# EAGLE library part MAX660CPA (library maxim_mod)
Charge-pump VOLTAGE CONVERTER

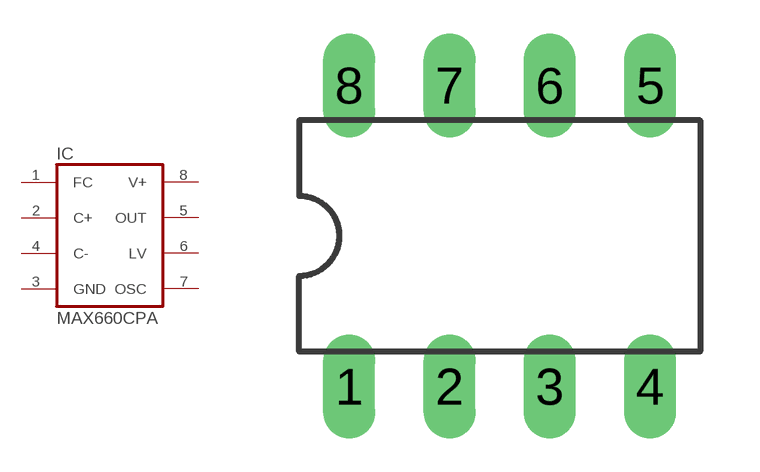
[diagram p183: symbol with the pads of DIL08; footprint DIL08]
Designator prefix IC

## MAX660CPA  [DIL08]
1  FC  in
2  C+  pas
3  GND  pwr
4  C-  pas
5  OUT  sup
6  LV  pas
7  OSC  out
8  V+  pwr

## Footprint DIL08 (pad centres in mm)
Dual In Line Package
drill 0.813 long: 1 -3.81,-3.81; 2 -1.27,-3.81; 3 1.27,-3.81; 4 3.81,-3.81; 5 3.81,3.81; 6 1.27,3.81; 7 -1.27,3.81; 8 -3.81,3.81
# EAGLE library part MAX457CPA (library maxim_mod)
VIDEO AMPLIFIER

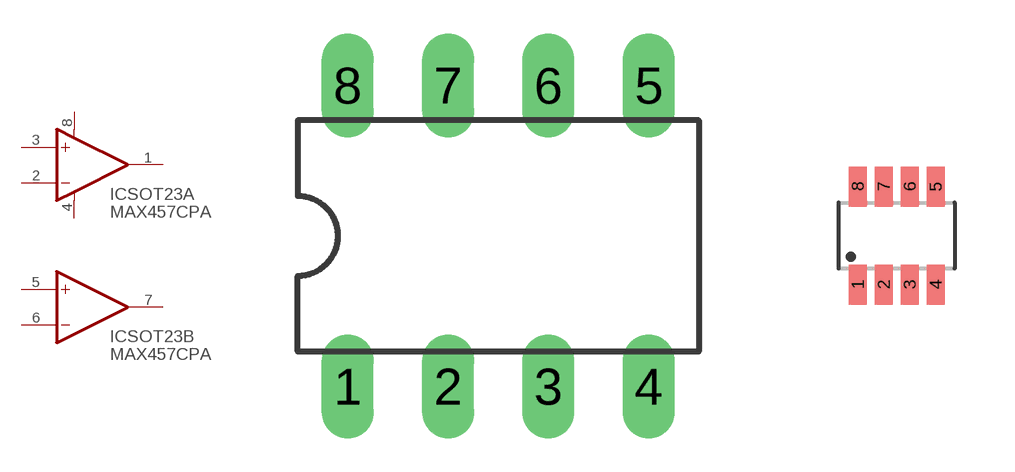
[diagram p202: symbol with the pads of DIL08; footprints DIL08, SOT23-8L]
Designator prefix ICSOT23; gates A=OPUB B=OP

## MAX457CPA  [DIL08]
1  A:OUT  out
2  A:-IN  in
3  A:+IN  in
4  A:V-  pwr
5  B:+IN  in
6  B:-IN  in
7  B:OUT  out
8  A:V+  pwr

## MAX457CPASOT23_8  [SOT23-8L]
Pads as for DIL08

## Footprint DIL08 (pad centres in mm)
Dual In Line Package
drill 0.813 long: 1 -3.81,-3.81; 2 -1.27,-3.81; 3 1.27,-3.81; 4 3.81,-3.81; 5 3.81,3.81; 6 1.27,3.81; 7 -1.27,3.81; 8 -3.81,3.81

## Footprint SOT23-8L (pad centres in mm)
SC70/SOT23-8 Source: http://datasheets.maxim-ic.com/en/ds/MAX4335-MAX4338.pdf
smd 0.45 x 1: 1 -0.975,-1.225; 2 -0.325,-1.225; 3 0.325,-1.225; 4 0.975,-1.225; 5 0.975,1.225; 6 0.325,1.225; 7 -0.325,1.225; 8 -0.975,1.225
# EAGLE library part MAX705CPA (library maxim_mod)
WATCHDOG

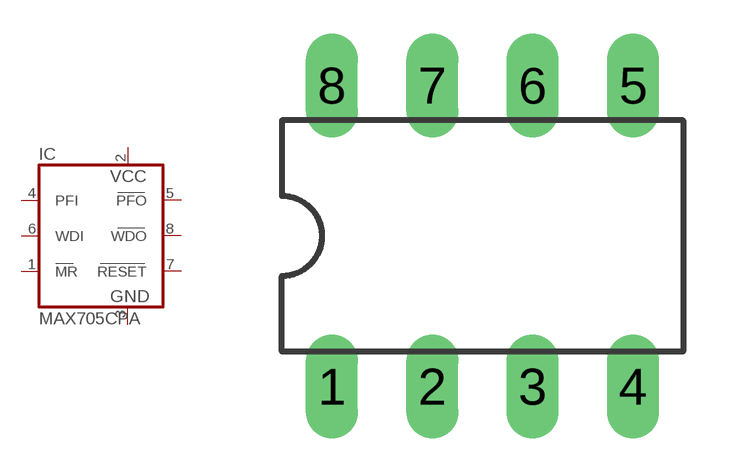
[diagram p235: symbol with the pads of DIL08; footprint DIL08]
Designator prefix IC

## MAX705CPA  [DIL08]
1  MR  in
2  VCC  pwr
3  GND  pwr
4  PFI  in
5  PFO  out
6  WDI  in
7  RESET  out
8  WDO  out

## Footprint DIL08 (pad centres in mm)
Dual In Line Package
drill 0.813 long: 1 -3.81,-3.81; 2 -1.27,-3.81; 3 1.27,-3.81; 4 3.81,-3.81; 5 3.81,3.81; 6 1.27,3.81; 7 -1.27,3.81; 8 -3.81,3.81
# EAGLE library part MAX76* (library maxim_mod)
DC-DC CONVERTER

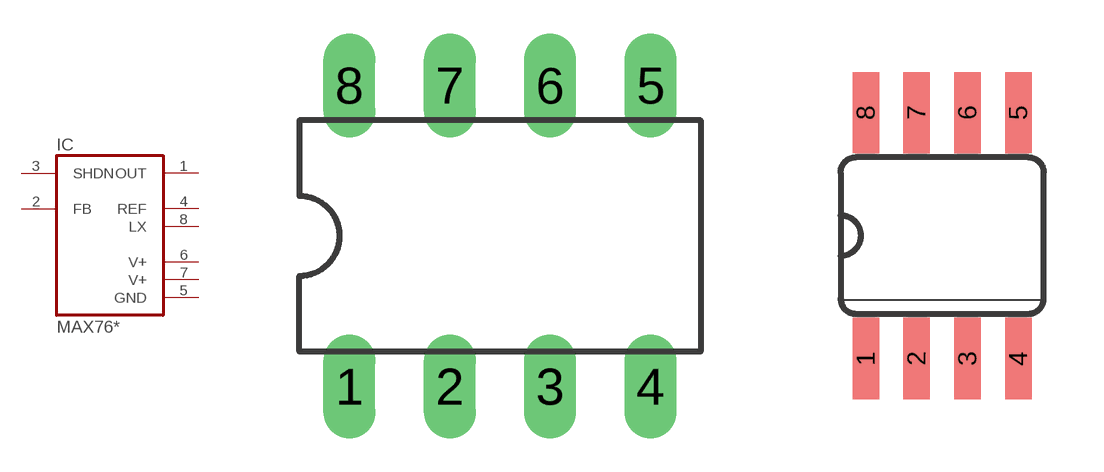
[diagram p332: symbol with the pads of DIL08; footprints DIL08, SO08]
Designator prefix IC

## MAX764CPA, MAX764EPA, MAX765CPA, MAX765EPA, MAX766CPA, MAX766EPA  [DIL08]
1  OUT  out
2  FB  in
3  SHDN  in
4  REF  out
5  GND  pwr
6  V+  pwr
7  V+  pwr
8  LX  out

## MAX764CSA, MAX764ESA, MAX765CSA, MAX765ESA, MAX766CSA, MAX766ESA  [SO08]
Pads as for DIL08

## Footprint DIL08 (pad centres in mm)
Dual In Line Package
drill 0.813 long: 1 -3.81,-3.81; 2 -1.27,-3.81; 3 1.27,-3.81; 4 3.81,-3.81; 5 3.81,3.81; 6 1.27,3.81; 7 -1.27,3.81; 8 -3.81,3.81

## Footprint SO08 (pad centres in mm)
Small Outline Package SOIC 150 mil
smd 0.66 x 2.032: 1 -1.905,-3.073; 2 -0.635,-3.073; 3 0.635,-3.073; 4 1.905,-3.073; 5 1.905,3.073; 6 0.635,3.073; 7 -0.635,3.073; 8 -1.905,3.073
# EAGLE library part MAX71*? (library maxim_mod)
NiCd/NiMH Battery Fast-Charge Controller

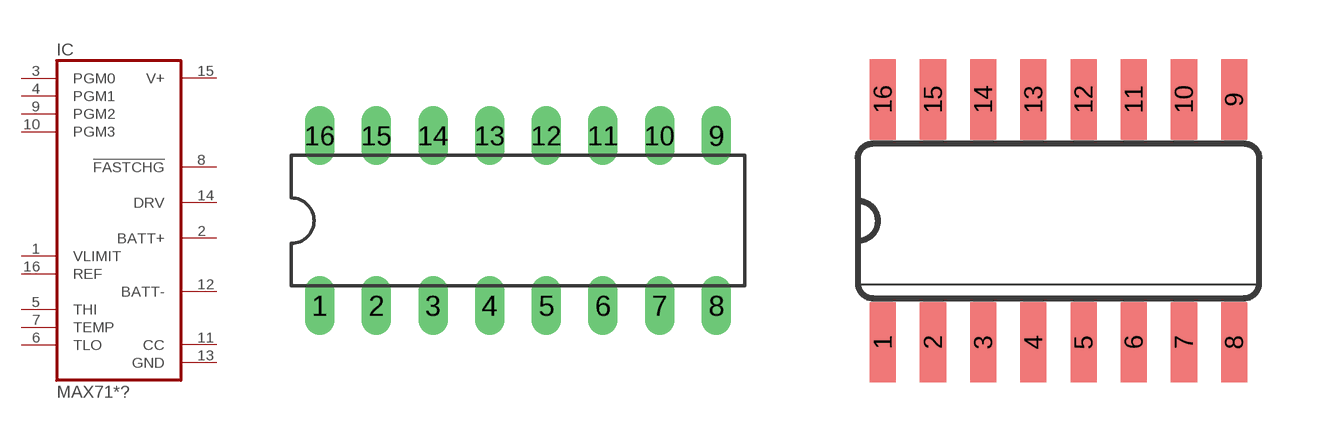
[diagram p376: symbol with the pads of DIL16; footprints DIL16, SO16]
Designator prefix IC

## MAX712CPE, MAX712EPE, MAX713CPE, MAX713EPE  [DIL16]
1  VLIMIT  in
2  BATT+  in
3  PGM0  in
4  PGM1  in
5  THI  in
6  TLO  in
7  TEMP  in
8  !FASTCHG  oc
9  PGM2  in
10  PGM3  in
11  CC  in
12  BATT-  in
13  GND  pwr
14  DRV  out
15  V+  pwr
16  REF  in

## MAX712CSE, MAX712ESE, MAX713CSE, MAX713ESE  [SO16]
Pads as for DIL16

## Footprint DIL16 (pad centres in mm)
Dual In Line Package
drill 0.813 long: 1 -8.89,-3.81; 2 -6.35,-3.81; 3 -3.81,-3.81; 4 -1.27,-3.81; 5 1.27,-3.81; 6 3.81,-3.81; 7 6.35,-3.81; 8 8.89,-3.81; 9 8.89,3.81; 10 6.35,3.81; 11 3.81,3.81; 12 1.27,3.81; 13 -1.27,3.81; 14 -3.81,3.81; 15 -6.35,3.81; 16 -8.89,3.81

## Footprint SO16 (pad centres in mm)
Small Outline Package .150 SIOC Source: http://www.maxim-ic.com/package_drawings/21-0041B.pdf
smd 0.66 x 2.032: 1 -4.445,-3.073; 2 -3.175,-3.073; 3 -1.905,-3.073; 4 -0.635,-3.073; 5 0.635,-3.073; 6 1.905,-3.073; 7 3.175,-3.073; 8 4.445,-3.073; 9 4.445,3.073; 10 3.175,3.073; 11 1.905,3.073; 12 0.635,3.073; 13 -0.635,3.073; 14 -1.905,3.073; 15 -3.175,3.073; 16 -4.445,3.073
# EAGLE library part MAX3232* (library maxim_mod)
True RS-232 Transceivers 3.0V to 5.5V, Low-Power up to 1Mbps, Using Four 0.1µF External Capacitors Source: http://pdfserv.maxim-ic.com/en/ds/MAX3222-MAX3241.pdf

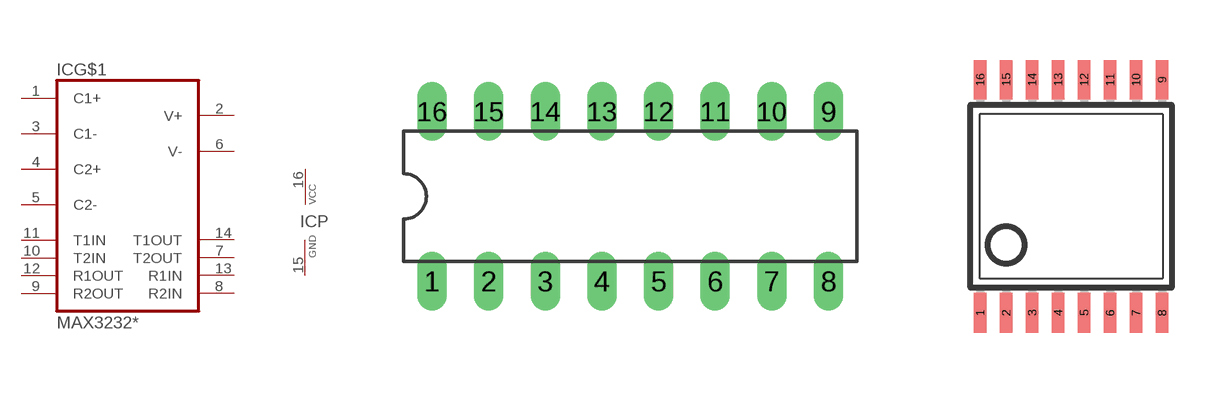
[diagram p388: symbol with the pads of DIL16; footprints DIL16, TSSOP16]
Designator prefix IC; gates G$1=MAX232 P=VCC-GND

## MAX3232CPE, MAX3232EPE  [DIL16]
1  G$1:C1+
2  G$1:V+
3  G$1:C1-
4  G$1:C2+
5  G$1:C2-
6  G$1:V-
7  G$1:T2OUT  out
8  G$1:R2IN  in
9  G$1:R2OUT  out
10  G$1:T2IN  in
11  G$1:T1IN  in
12  G$1:R1OUT  out
13  G$1:R1IN  in
14  G$1:T1OUT  out
15  P:GND  pwr
16  P:VCC  pwr

## MAX3232CUE, MAX3232EUE  [TSSOP16]
Pads as for DIL16

## MAX3232CWE, MAX3232EWE  [SO16L]
Pads as for DIL16

## MAX3232CSE, MAX3232ESE  [SO16]
Pads as for DIL16

## Footprint DIL16 (pad centres in mm)
Dual In Line Package
drill 0.813 long: 1 -8.89,-3.81; 2 -6.35,-3.81; 3 -3.81,-3.81; 4 -1.27,-3.81; 5 1.27,-3.81; 6 3.81,-3.81; 7 6.35,-3.81; 8 8.89,-3.81; 9 8.89,3.81; 10 6.35,3.81; 11 3.81,3.81; 12 1.27,3.81; 13 -1.27,3.81; 14 -3.81,3.81; 15 -6.35,3.81; 16 -8.89,3.81

## Footprint TSSOP16 (pad centres in mm)
Thin Shrink Small Outline Plastic 16 http://www.maxim-ic.com .. MAX3223-MAX3243.pdf
smd 0.305 x 0.991: 1 -2.275,-2.918; 2 -1.625,-2.918; 3 -0.975,-2.918; 4 -0.325,-2.918; 5 0.325,-2.918; 6 0.975,-2.918; 7 1.625,-2.918; 8 2.275,-2.918; 9 2.275,2.918; 10 1.625,2.918; 11 0.975,2.918; 12 0.325,2.918; 13 -0.325,2.918; 14 -0.975,2.918; 15 -1.625,2.918; 16 -2.275,2.918

## Footprint SO16L (pad centres in mm)
Small Outline Package .300 SIOC Source: http://www.maxim-ic.com/cgi-bin/packages?pkg=16%2FSOIC%2E300&Type=Max
smd 0.66 x 2.032: 1 -4.445,-4.902; 2 -3.175,-4.902; 3 -1.905,-4.902; 4 -0.635,-4.902; 5 0.635,-4.902; 6 1.905,-4.902; 7 3.175,-4.902; 8 4.445,-4.902; 9 4.445,4.902; 10 3.175,4.902; 11 1.905,4.902; 12 0.635,4.902; 13 -0.635,4.902; 14 -1.905,4.902; 15 -3.175,4.902; 16 -4.445,4.902

## Footprint SO16 (pad centres in mm)
Small Outline Package .150 SIOC Source: http://www.maxim-ic.com/package_drawings/21-0041B.pdf
smd 0.66 x 2.032: 1 -4.445,-3.073; 2 -3.175,-3.073; 3 -1.905,-3.073; 4 -0.635,-3.073; 5 0.635,-3.073; 6 1.905,-3.073; 7 3.175,-3.073; 8 4.445,-3.073; 9 4.445,3.073; 10 3.175,3.073; 11 1.905,3.073; 12 0.635,3.073; 13 -0.635,3.073; 14 -1.905,3.073; 15 -3.175,3.073; 16 -4.445,3.073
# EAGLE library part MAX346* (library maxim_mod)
+5V, Fail-Safe, 40Mbps, Profibus RS-485/RS-422 Transceivers Source: MAX3465-MAX3469.pdf

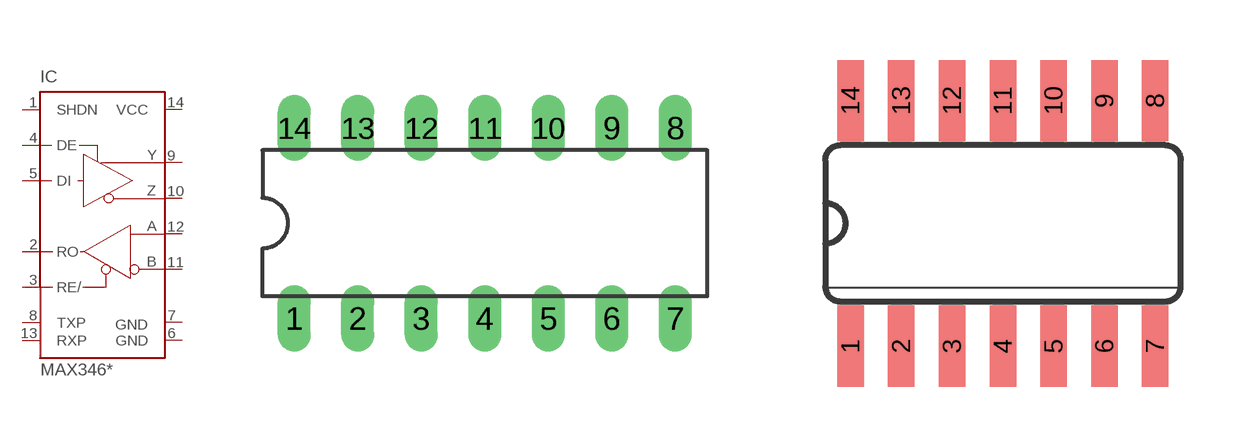
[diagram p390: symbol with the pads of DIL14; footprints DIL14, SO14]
Designator prefix IC

## MAX3465CPD, MAX3465EPD, MAX3466CPD, MAX3466EPD  [DIL14]
1  SHDN  in
2  RO  out
3  RE/  in
4  DE  in
5  DI  in
6  GND  pwr
7  GND  pwr
8  TXP  pas
9  Y  out
10  Z  out
11  B  in
12  A  in
13  RXP  pas
14  VCC  pwr

## MAX3465CSD, MAX3465ESD, MAX3466CSD, MAX3466ESD  [SO14]
Pads as for DIL14

## Footprint DIL14 (pad centres in mm)
Dual In Line Package
drill 0.813 long: 1 -7.62,-3.81; 2 -5.08,-3.81; 3 -2.54,-3.81; 4 0,-3.81; 5 2.54,-3.81; 6 5.08,-3.81; 7 7.62,-3.81; 8 7.62,3.81; 9 5.08,3.81; 10 2.54,3.81; 11 0,3.81; 12 -2.54,3.81; 13 -5.08,3.81; 14 -7.62,3.81

## Footprint SO14 (pad centres in mm)
Small Outline Package
smd 0.66 x 2.032: 1 -3.81,-3.073; 2 -2.54,-3.073; 3 -1.27,-3.073; 4 0,-3.073; 5 1.27,-3.073; 6 2.54,-3.073; 7 3.81,-3.073; 8 3.81,3.073; 9 2.54,3.073; 10 1.27,3.073; 11 0,3.073; 12 -1.27,3.073; 13 -2.54,3.073; 14 -3.81,3.073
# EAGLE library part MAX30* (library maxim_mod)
±10kV ESD-Protected, Quad 5V RS-485/RS-422 Transmitters Source: www.maxim-ic.com .. MAX3040-MAX3045.pdf

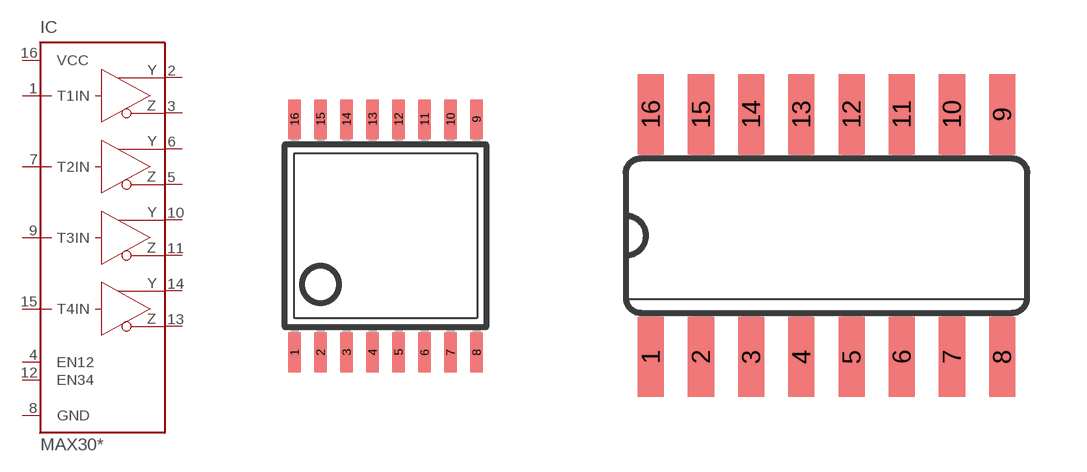
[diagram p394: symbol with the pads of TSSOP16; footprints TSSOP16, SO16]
Designator prefix IC

## MAX3040CUE, MAX3040EUE, MAX3041CUE, MAX3041EUE, MAX3042BCUE, MAX3042BEUE  [TSSOP16]
1  T1IN  in
2  Y1  out
3  Z1  out
4  EN12  in
5  Z2  out
6  Y2  out
7  T2IN  in
8  GND  pwr
9  T3IN  in
10  Y3  out
11  Z3  out
12  EN34  in
13  Z4  out
14  Y4  out
15  T4IN  in
16  VCC  pwr

## MAX3040CSE, MAX3040ESE, MAX3041CSE, MAX3041ESE, MAX3042BCSE, MAX3042BESE  [SO16]
Pads as for TSSOP16

## MAX3040CWE, MAX3040EWE, MAX3041CWE, MAX3041EWE, MAX3042BCWE, MAX3042BEWE  [SO16L]
Pads as for TSSOP16

## Footprint TSSOP16 (pad centres in mm)
Thin Shrink Small Outline Plastic 16 http://www.maxim-ic.com .. MAX3223-MAX3243.pdf
smd 0.305 x 0.991: 1 -2.275,-2.918; 2 -1.625,-2.918; 3 -0.975,-2.918; 4 -0.325,-2.918; 5 0.325,-2.918; 6 0.975,-2.918; 7 1.625,-2.918; 8 2.275,-2.918; 9 2.275,2.918; 10 1.625,2.918; 11 0.975,2.918; 12 0.325,2.918; 13 -0.325,2.918; 14 -0.975,2.918; 15 -1.625,2.918; 16 -2.275,2.918

## Footprint SO16 (pad centres in mm)
Small Outline Package .150 SIOC Source: http://www.maxim-ic.com/package_drawings/21-0041B.pdf
smd 0.66 x 2.032: 1 -4.445,-3.073; 2 -3.175,-3.073; 3 -1.905,-3.073; 4 -0.635,-3.073; 5 0.635,-3.073; 6 1.905,-3.073; 7 3.175,-3.073; 8 4.445,-3.073; 9 4.445,3.073; 10 3.175,3.073; 11 1.905,3.073; 12 0.635,3.073; 13 -0.635,3.073; 14 -1.905,3.073; 15 -3.175,3.073; 16 -4.445,3.073

## Footprint SO16L (pad centres in mm)
Small Outline Package .300 SIOC Source: http://www.maxim-ic.com/cgi-bin/packages?pkg=16%2FSOIC%2E300&Type=Max
smd 0.66 x 2.032: 1 -4.445,-4.902; 2 -3.175,-4.902; 3 -1.905,-4.902; 4 -0.635,-4.902; 5 0.635,-4.902; 6 1.905,-4.902; 7 3.175,-4.902; 8 4.445,-4.902; 9 4.445,4.902; 10 3.175,4.902; 11 1.905,4.902; 12 0.635,4.902; 13 -0.635,4.902; 14 -1.905,4.902; 15 -3.175,4.902; 16 -4.445,4.902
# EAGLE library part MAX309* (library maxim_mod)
±15kV ESD-Protected, 10Mbps, 3V/5V, Quad RS-422/RS-485 Receivers Source: http://pdfserv.maxim-ic.com/en/ds/MAX3095-MAX3096.pdf

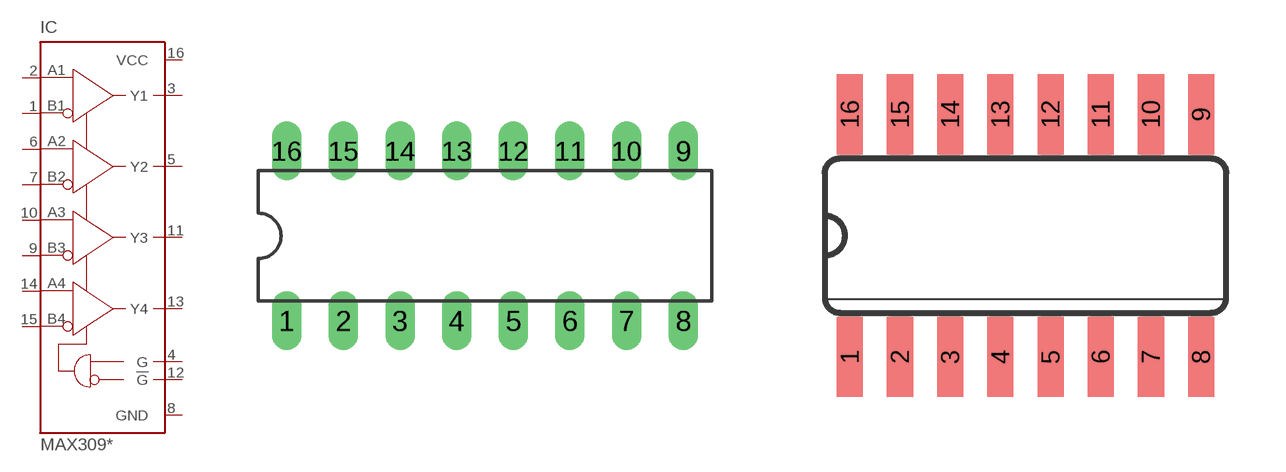
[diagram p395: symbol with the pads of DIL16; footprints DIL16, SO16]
Designator prefix IC

## MAX3095CPE, MAX3095EPE, MAX3096CPE, MAX3096EPE  [DIL16]
1  B1  out
2  A1  out
3  Y1  out
4  G  in
5  Y2  out
6  A2  out
7  B2  out
8  GND  pwr
9  B3  out
10  A3  out
11  Y3  out
12  !G  in
13  Y4  out
14  A4  out
15  B4  out
16  VCC  out

## MAX3095CSE, MAX3095ESE, MAX3096CSE, MAX3096ESE  [SO16]
Pads as for DIL16

## MAX3095CEE, MAX3095EEE, MAX3096CEE, MAX3096EEE  [QSOP16]
Pads as for DIL16

## Footprint DIL16 (pad centres in mm)
Dual In Line Package
drill 0.813 long: 1 -8.89,-3.81; 2 -6.35,-3.81; 3 -3.81,-3.81; 4 -1.27,-3.81; 5 1.27,-3.81; 6 3.81,-3.81; 7 6.35,-3.81; 8 8.89,-3.81; 9 8.89,3.81; 10 6.35,3.81; 11 3.81,3.81; 12 1.27,3.81; 13 -1.27,3.81; 14 -3.81,3.81; 15 -6.35,3.81; 16 -8.89,3.81

## Footprint SO16 (pad centres in mm)
Small Outline Package .150 SIOC Source: http://www.maxim-ic.com/package_drawings/21-0041B.pdf
smd 0.66 x 2.032: 1 -4.445,-3.073; 2 -3.175,-3.073; 3 -1.905,-3.073; 4 -0.635,-3.073; 5 0.635,-3.073; 6 1.905,-3.073; 7 3.175,-3.073; 8 4.445,-3.073; 9 4.445,3.073; 10 3.175,3.073; 11 1.905,3.073; 12 0.635,3.073; 13 -0.635,3.073; 14 -1.905,3.073; 15 -3.175,3.073; 16 -4.445,3.073

## Footprint QSOP16 (pad centres in mm)
Small Outline Package
smd 0.45 x 1.5: 1 -2.223,-2.69; 2 -1.587,-2.69; 3 -0.953,-2.69; 4 -0.318,-2.69; 5 0.318,-2.69; 6 0.953,-2.69; 7 1.587,-2.69; 8 2.223,-2.69; 9 2.223,2.69; 10 1.587,2.69; 11 0.953,2.69; 12 0.318,2.69; 13 -0.318,2.69; 14 -0.953,2.69; 15 -1.587,2.69; 16 -2.223,2.69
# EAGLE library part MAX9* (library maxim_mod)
Micropower, Low-Voltage Rail-to-Rail I/O Comparators Source: http://pdfserv.maxim-ic.com/en/ds/MAX985-MAX994.pdf

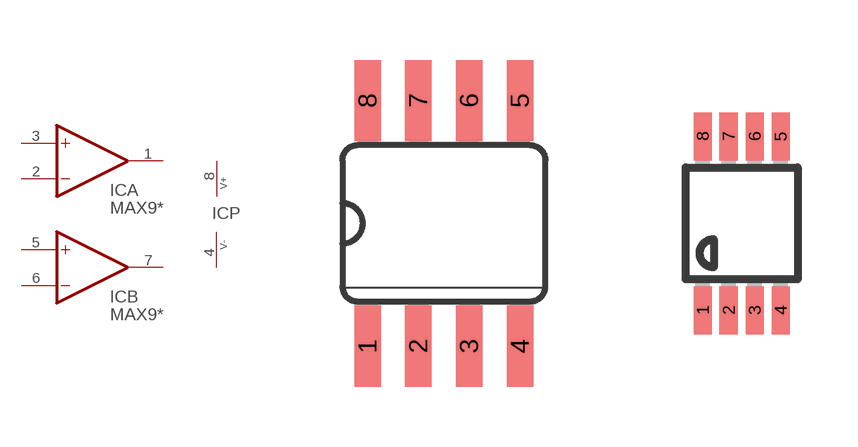
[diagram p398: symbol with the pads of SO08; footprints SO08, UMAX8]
Designator prefix IC; gates A=OP B=OP P=PWR+-

## MAX989ESA, MAX990ESA  [SO08]
1  A:OUT  out
2  A:-IN  in
3  A:+IN  in
4  P:V-  pwr
5  B:+IN  in
6  B:-IN  in
7  B:OUT  out
8  P:V+  pwr

## MAX989EUA, MAX990EUA  [UMAX8]
Pads as for SO08

## Footprint SO08 (pad centres in mm)
Small Outline Package SOIC 150 mil
smd 0.66 x 2.032: 1 -1.905,-3.073; 2 -0.635,-3.073; 3 0.635,-3.073; 4 1.905,-3.073; 5 1.905,3.073; 6 0.635,3.073; 7 -0.635,3.073; 8 -1.905,3.073

## Footprint UMAX8 (pad centres in mm)
micro MAX Package
smd 0.45 x 1.2: 1 -0.975,-2.175; 2 -0.325,-2.175; 3 0.325,-2.175; 4 0.975,-2.175; 5 0.975,2.175; 6 0.325,2.175; 7 -0.325,2.175; 8 -0.975,2.175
